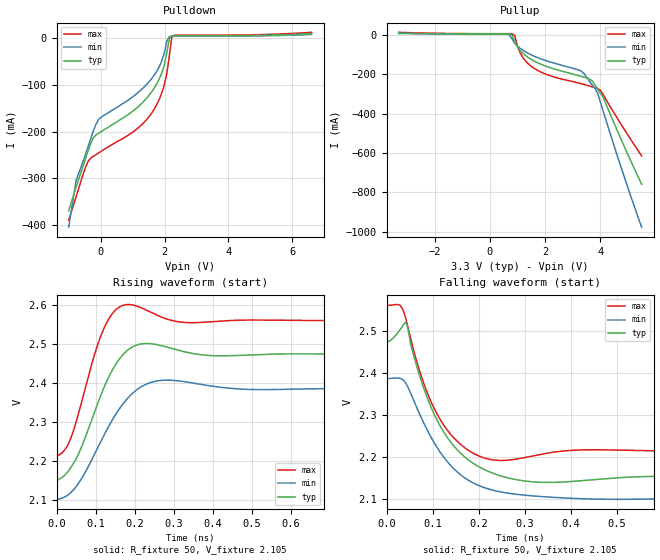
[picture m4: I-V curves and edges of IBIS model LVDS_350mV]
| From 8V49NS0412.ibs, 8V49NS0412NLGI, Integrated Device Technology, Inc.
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[Model]   LVDS_350mV
Model_type   Output
Polarity   Non-Inverting
|   typ   min   max
C_comp   2pF   1.5pF   2.5pF
Vmeas = 2.320V
Rref = 50
Cref = 0
Vref = 2.320V
|   typ   min   max
[Voltage range]   3.3V   3.135V   3.465V
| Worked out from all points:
|   slope of the pulldown table from 0 to 0.495 V, typ, clamps not added: 23.4 ohm
|   slope of the pullup table from 0 to 0.495 V, typ, clamps not added: 15.2 kohm
|   rising waveform, R_fixture 50, V_fixture 2.105: 20-80 % time 75.4ps typ, 91.6ps min, 58ps max; typ from 2.15 V to 2.47 V
|   falling waveform, R_fixture 50, V_fixture 2.105: 20-80 % time 86.4ps typ, 98.2ps min, 69.2ps max; typ from 2.47 V to 2.15 V
[Pulldown]
|Voltage   I (typ)   I (min)   I (max)
-1V       -369.2mA   -404mA     -389.3mA
-769.7mV  -318.7mA   -305.5mA   -339.7mA
-385.9mV  -239.3mA   -230.7mA   -262.7mA
-78.79mV  -204mA     -175.3mA   -246.1mA
996mV     -156.6mA   -125.8mA   -201.4mA
1.533V    -120.7mA   -91.73mA   -166.2mA
1.917V    -73.52mA   -48.04mA   -116.3mA
2.071V    -31.23mA   -6.795mA   -75.56mA
2.147V    -1.641mA   2.624mA    -38.4mA
2.224V    4.501mA    3.932mA    1.504mA
2.301V    4.927mA    4.059mA    6.09mA
6.6V      9.632mA    7.787mA    12.38mA
[Pullup]
|Voltage   I (typ)   I (min)   I (max)
-3.3V     9.632mA    7.309mA    13.15mA
600mV     4.967mA    3.931mA    6.255mA
800mV     1.365mA    -18.84mA   6.157mA
900mV     -31.37mA   -41.51mA   -1.956mA
1V        -59.83mA   -56.27mA   -55.59mA
1.2V      -93.01mA   -77.76mA   -115.2mA
1.5V      -124mA     -101mA     -159.1mA
3.3V      -210.2mA   -182.5mA   -247.3mA
3.7V      -232mA     -252.1mA   -263.2mA
3.9V      -273.3mA   -291.9mA   -271.5mA
4.1V      -313.8mA   -383.6mA   -300.7mA
5.5V      -758.3mA   -976.2mA   -614.1mA
[Ramp]
|   typ   min   max
dV/dt_r   0.209/0.084n   0.183/0.101n   0.232/0.067n
dV/dt_f   0.228/0.096n   0.173/0.101n   0.222/0.079n
R_load =   50.0000
[Rising Waveform]
R_fixture = 50
V_fixture   =2.105  |Vcc_typ
V_fixture_min=1.95  |Vcc_min
V_fixture_max=2.15  |Vcc_max
C_fixture = 0.0p
| Time   typ   min   max
0s        2.151V     2.101V     2.213V
38.04ps   2.184V     2.12V      2.262V
96.1ps    2.321V     2.214V     2.468V
122.1ps   2.389V     2.266V     2.54V
148.1ps   2.441V     2.313V     2.583V
176.2ps   2.478V     2.353V     2.6V
220.2ps   2.5V       2.391V     2.59V
280.3ps   2.492V     2.406V     2.564V
416.4ps   2.469V     2.389V     2.557V
2ns       2.473V     2.385V     2.559V
[Falling Waveform]
R_fixture = 50
V_fixture   =2.105  |Vcc_typ
V_fixture_min=1.95  |Vcc_min
V_fixture_max=2.15  |Vcc_max
C_fixture = 0.0p
| Time   typ   min   max
0s        2.474V     2.386V     2.56V
28.03ps   2.501V     2.387V     2.561V
42.04ps   2.519V     2.375V     2.528V
78.08ps   2.372V     2.287V     2.384V
118.1ps   2.27V      2.209V     2.286V
170.2ps   2.199V     2.15V      2.221V
230.2ps   2.161V     2.121V     2.193V
348.3ps   2.139V     2.104V     2.209V
600.6ps   2.154V     2.1V       2.214V
2ns       2.152V     2.102V     2.214V
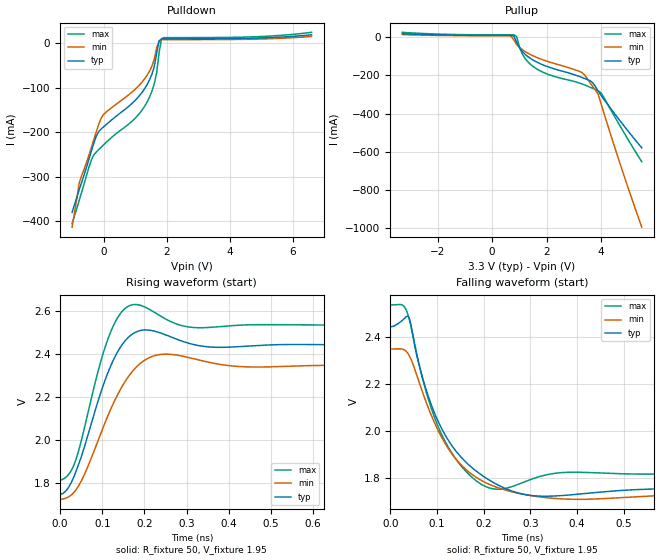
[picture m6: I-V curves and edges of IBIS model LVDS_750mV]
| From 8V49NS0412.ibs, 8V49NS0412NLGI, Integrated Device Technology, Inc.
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[Model]   LVDS_750mV
Model_type   Output
Polarity   Non-Inverting
|   typ   min   max
C_comp   2pF   1.5pF   2.5pF
Vmeas = 2.138V
Rref = 50
Cref = 0
Vref = 2.138V
|   typ   min   max
[Voltage range]   3.3V   3.135V   3.465V
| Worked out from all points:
|   slope of the pulldown table from 0 to 0.495 V, typ, clamps not added: 16.9 ohm
|   slope of the pullup table from 0 to 0.495 V, typ, clamps not added: 7.22 kohm
|   rising waveform, R_fixture 50, V_fixture 1.95: 20-80 % time 67ps typ, 79.6ps min, 55ps max; typ from 1.75 V to 2.44 V
|   falling waveform, R_fixture 50, V_fixture 1.95: 20-80 % time 91.2ps typ, 95.3ps min, 66.1ps max; typ from 2.44 V to 1.75 V
[Pulldown]
|Voltage   I (typ)   I (min)   I (max)
-1V       -380mA     -413.5mA   -405.5mA
-769.7mV  -328.1mA   -312.7mA   -351.9mA
-385.9mV  -241.5mA   -233.6mA   -261.8mA
-232.3mV  -208.5mA   -198.5mA   -244.3mA
-78.79mV  -192.7mA   -168.3mA   -233.6mA
1.303V    -101.7mA   -79.42mA   -141.3mA
1.61V     -51.32mA   -35.06mA   -89.79mA
1.687V    -19.97mA   -8.889mA   -64.63mA
1.764V    6.109mA    5.691mA    -18.81mA
1.84V     10.09mA    8.231mA    11.05mA
1.917V    10.34mA    8.49mA     12.96mA
6.6V      19.39mA    15.63mA    24.98mA
[Pullup]
|Voltage   I (typ)   I (min)   I (max)
-3.3V     19.39mA    14.69mA    26.51mA
600mV     10.43mA    8.42mA     13.14mA
800mV     6.88mA     -13.92mA   13.02mA
900mV     -25.73mA   -36.81mA   4.928mA
1V        -54.29mA   -51.64mA   -48.7mA
1.2V      -87.52mA   -73.19mA   -108.4mA
1.5V      -118.6mA   -96.51mA   -152.2mA
3.3V      -210.1mA   -184.3mA   -244.5mA
3.7V      -238.3mA   -258.5mA   -268mA
3.9V      -282.5mA   -300mA     -280.6mA
4.7V      -437.8mA   -662mA     -464.6mA
5.5V      -579.8mA   -996.1mA   -652.9mA
[Ramp]
|   typ   min   max
dV/dt_r   0.457/0.076n   0.405/0.089n   0.488/0.065n
dV/dt_f   0.46/0.102n   0.384/0.102n   0.471/0.079n
R_load =   50.0000
[Rising Waveform]
R_fixture = 50
V_fixture   =1.95  |Vcc_typ
V_fixture_min=1.75  |Vcc_min
V_fixture_max=2.15  |Vcc_max
C_fixture = 0.0p
| Time   typ   min   max
0s        1.753V     1.725V     1.816V
36.04ps   1.846V     1.765V     1.901V
92.09ps   2.196V     2.009V     2.336V
120.1ps   2.346V     2.145V     2.505V
146.1ps   2.442V     2.247V     2.597V
172.2ps   2.494V     2.322V     2.63V
234.2ps   2.501V     2.397V     2.581V
326.3ps   2.44V      2.374V     2.523V
460.5ps   2.439V     2.34V      2.537V
2ns       2.443V     2.347V     2.535V
[Falling Waveform]
R_fixture = 50
V_fixture   =1.95  |Vcc_typ
V_fixture_min=1.75  |Vcc_min
V_fixture_max=2.15  |Vcc_max
C_fixture = 0.0p
| Time   typ   min   max
0s        2.444V     2.35V      2.537V
26.03ps   2.472V     2.349V     2.536V
40.04ps   2.482V     2.323V     2.481V
76.08ps   2.18V      2.127V     2.172V
122.1ps   1.968V     1.932V     1.939V
170.2ps   1.853V     1.823V     1.812V
220.2ps   1.782V     1.767V     1.754V
292.3ps   1.729V     1.728V     1.788V
386.4ps   1.729V     1.71V      1.825V
2ns       1.755V     1.727V     1.818V
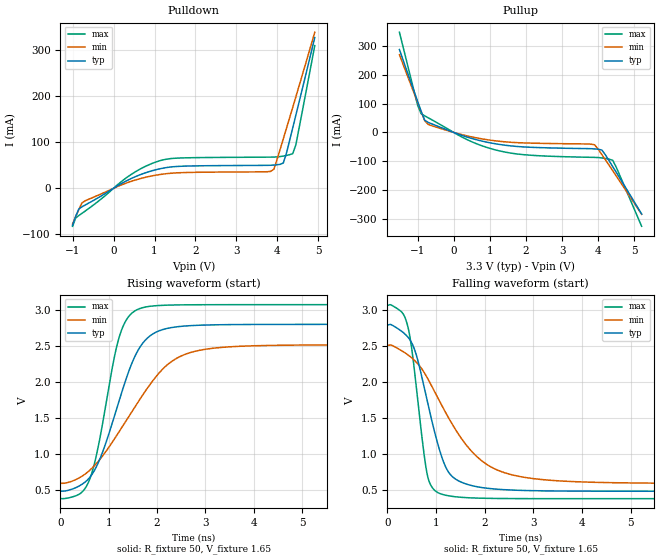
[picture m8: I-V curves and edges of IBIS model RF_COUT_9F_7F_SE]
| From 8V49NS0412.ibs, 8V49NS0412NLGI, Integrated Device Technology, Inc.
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[Model]   RF_COUT_9F_7F_SE
Model_type   Output
Polarity   Non-Inverting
|   typ   min   max
C_comp   2pF   1.5pF   2.5pF
Vmeas = 1.65V
Rref = 50
Cref = 0
Vref = 1.65V
|   typ   min   max
[Voltage range]   3.3V   3.135V   3.465V
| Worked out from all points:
|   slope of the pulldown table from 0 to 0.495 V, typ, clamps not added: 20.8 ohm
|   slope of the pullup table from 0 to 0.495 V, typ, clamps not added: 23.8 ohm
|   rising waveform, R_fixture 50, V_fixture 1.65: 20-80 % time 701ps typ, 1.17ns min, 458ps max; typ from 0.483 V to 2.79 V
|   falling waveform, R_fixture 50, V_fixture 1.65: 20-80 % time 512ps typ, 1.06ns min, 283ps max; typ from 2.79 V to 0.483 V
[Pulldown]
|Voltage   I (typ)   I (min)   I (max)
|Note, modeling breaks down at 250mA and above.  This is well beyond the functional   |
|operating range of the device.  Should this scenario occur, catastrophic failure and   |
|possible damage to the device and/or board is of higher concern than the I-V curve   |
|behavior.  The IBIS checker will flag currents in excess of 10A with warnings.  Lines   |
|with currents in excess of 0.35 A have been commented out.  The points still remain|
|available to the user if the user desires to use them.   |
|Note, modeling breaks down at 250mA and above.  This is well beyond the functional   |
|operating range of the device.  Should this scenario occur, catastrophic failure and   |
|possible damage to the device and/or board is of higher concern than the I-V curve   |
|behavior.  The IBIS checker will flag currents in excess of 10A with warnings.  Lines   |
|with currents in excess of 0.35 A have been commented out.  The points still remain|
|available to the user if the user desires to use them.   |
-1V       -80.01mA   -77.39mA   -82.42mA
-923.2mV  -60.69mA   -61.48mA   -64.31mA
-846.5mV  -44.85mA   -45.55mA   -59.05mA
-692.9mV  -36.28mA   -27.09mA   -49.43mA
381.8mV   19.16mA    13.65mA    27.17mA
1.073V    41.15mA    29.07mA    58.25mA
1.61V     47.69mA    33.79mA    65.71mA
3.913V    50.42mA    41.44mA    67.79mA
4.143V    55mA       107.4mA    69.96mA
4.374V    131.2mA    175.8mA    75.2mA
4.451V    158.9mA    198.7mA    94.62mA
4.911V    327mA      338.5mA    309.5mA
|| 4.98788e+00   3.55369e-01   3.62098e-01   3.45717e-01
|| 5.06465e+00   3.83846e-01   3.85830e-01   3.82046e-01
|| 5.14141e+00   4.12429e-01   4.09675e-01   4.18481e-01
|| 5.21818e+00   4.41121e-01   4.33643e-01   4.55023e-01
|| 5.29495e+00   4.69927e-01   4.57741e-01   4.91672e-01
|| 5.37172e+00   4.98853e-01   4.81982e-01   5.28433e-01
|| 5.44848e+00   5.27906e-01   5.06377e-01   5.65308e-01
|| 5.52525e+00   5.57095e-01   5.30941e-01   6.02303e-01
|| 5.60202e+00   5.86428e-01   5.55693e-01   6.39424e-01
|| 5.67879e+00   6.15919e-01   5.80653e-01   6.76679e-01
|| 5.75556e+00   6.45578e-01   6.05845e-01   7.14075e-01
|| 5.83232e+00   6.75422e-01   6.31297e-01   7.51623e-01
|| 5.90909e+00   7.05468e-01   6.57044e-01   7.89333e-01
|| 5.98586e+00   7.35735e-01   6.83124e-01   8.27218e-01
|| 6.06263e+00   7.66248e-01   7.09586e-01   8.65292e-01
|| 6.13939e+00   7.97032e-01   7.36483e-01   9.03570e-01
|| 6.21616e+00   8.28120e-01   7.63880e-01   9.42072e-01
|| 6.29293e+00   8.59548e-01   7.91844e-01   9.80818e-01
|| 6.36970e+00   8.91358e-01   8.20439e-01   1.01983e+00
|| 6.44646e+00   9.23602e-01   8.49697e-01   1.05914e+00
|| 6.52323e+00   9.56338e-01   8.79569e-01   1.09877e+00
|| 6.60000e+00   9.89634e-01   9.09969e-01   1.13877e+00
[Pullup]
|Voltage   I (typ)   I (min)   I (max)
|Note, modeling breaks down at 250mA and above.  This is well beyond the functional   |
|operating range of the device.  Should this scenario occur, catastrophic failure and   |
|possible damage to the device and/or board is of higher concern than the I-V curve   |
|behavior.  The IBIS checker will flag currents in excess of 10A with warnings.  Lines   |
|with currents in excess of 0.35 A have been commented out.  The points still remain|
|available to the user if the user desires to use them.   |
|-3.30000e+00   9.45857e-01   8.75303e-01   1.27117e+00
|-3.20000e+00   9.09588e-01   8.41674e-01   1.22056e+00
|-3.10000e+00   8.73366e-01   8.08121e-01   1.16996e+00
|-3.00000e+00   8.37177e-01   7.74635e-01   1.11936e+00
|-2.90000e+00   8.01009e-01   7.41201e-01   1.06874e+00
|-2.80000e+00   7.64851e-01   7.07805e-01   1.01810e+00
|-2.70000e+00   7.28692e-01   6.74437e-01   9.67395e-01
|-2.60000e+00   6.92523e-01   6.41088e-01   9.16593e-01
|-2.50000e+00   6.56325e-01   6.07748e-01   8.65519e-01
|-2.40000e+00   6.20062e-01   5.74411e-01   8.13176e-01
|-2.30000e+00   5.83594e-01   5.41061e-01   7.60402e-01
|-2.20000e+00   5.46132e-01   5.07670e-01   7.07979e-01
|-2.10000e+00   5.08522e-01   4.74113e-01   6.55878e-01
|-2.00000e+00   4.71209e-01   4.39722e-01   6.04068e-01
|-1.90000e+00   4.34167e-01   4.05325e-01   5.52519e-01
|-1.80000e+00   3.97370e-01   3.71202e-01   5.01202e-01
|-1.70000e+00   3.60796e-01   3.37331e-01   4.50088e-01
|-1.60000e+00   3.24420e-01   3.03688e-01   3.99149e-01
-1.5V     288.2mA    270.3mA    348.4mA
-1V       109.2mA    105.5mA    95.76mA
-900mV    73.61mA    72.9mA     64.87mA
-800mV    42.22mA    40.41mA    57.54mA
-700mV    34.5mA     27.43mA    50.55mA
400mV     -17.28mA   -12.96mA   -26.81mA
1.2V      -40.51mA   -29.96mA   -62.27mA
2.1V      -51.52mA   -37.13mA   -79.12mA
3.9V      -57.37mA   -43.21mA   -86.91mA
4.1V      -61.33mA   -77.21mA   -88.74mA
4.4V      -119mA     -133.1mA   -96.78mA
5.2V      -283.8mA   -285.1mA   -326.7mA
| 5.30000e+00   -3.04576e-01   -3.04296e-01   -3.56043e-01
| 5.40000e+00   -3.25392e-01   -3.23523e-01   -3.85446e-01
| 5.50000e+00   -3.46244e-01   -3.42791e-01   -4.14886e-01
| 5.60000e+00   -3.67138e-01   -3.62103e-01   -4.44370e-01
| 5.70000e+00   -3.88076e-01   -3.81462e-01   -4.73908e-01
| 5.80000e+00   -4.09065e-01   -4.00872e-01   -5.03509e-01
| 5.90000e+00   -4.30112e-01   -4.20339e-01   -5.33184e-01
| 6.00000e+00   -4.51223e-01   -4.39868e-01   -5.62945e-01
| 6.10000e+00   -4.72405e-01   -4.59465e-01   -5.92805e-01
| 6.20000e+00   -4.93669e-01   -4.79137e-01   -6.22775e-01
| 6.30000e+00   -5.15022e-01   -4.98891e-01   -6.52870e-01
| 6.40000e+00   -5.36474e-01   -5.18735e-01   -6.83105e-01
| 6.50000e+00   -5.58035e-01   -5.38676e-01   -7.13493e-01
| 6.60000e+00   -5.79716e-01   -5.58723e-01   -7.44050e-01
[Ramp]
|   typ   min   max
dV/dt_r   1.386/0.701n   1.151/1.172n   1.612/0.457n
dV/dt_f   1.39/0.513n   1.154/1.062n   1.617/0.284n
R_load =   50.0000
[Rising Waveform]
R_fixture = 50
V_fixture = 1.65   |Vcc_typ
V_fixture_min = 1.5675 |Vcc_min
V_fixture_max = 1.7325 |Vcc_max
C_fixture = 0.0p
| Time   typ   min   max
0s        482.9mV    591.7mV    379.9mV
378.4ps   551.8mV    664mV      437.6mV
576.6ps   650.7mV    755mV      601.7mV
756.8ps   840mV      876.5mV    1.019V
1.225ns   1.76V      1.319V     2.638V
1.423ns   2.161V     1.53V      2.912V
1.73ns    2.555V     1.843V     3.03V
2.432ns   2.762V     2.334V     3.064V
3.514ns   2.791V     2.484V     3.067V
18ns      2.794V     2.511V     3.067V
[Falling Waveform]
R_fixture = 50
V_fixture = 1.65   |Vcc_typ
V_fixture_min = 1.5675 |Vcc_min
V_fixture_max = 1.7325 |Vcc_max
C_fixture = 0.0p
| Time   typ   min   max
0s        2.794V     2.511V     3.067V
396.4ps   2.645V     2.391V     2.833V
486.5ps   2.564V     2.345V     2.539V
576.6ps   2.42V      2.29V      2.049V
828.8ps   1.714V     2.051V     691.1mV
955ps     1.352V     1.89V      508.1mV
1.207ns   809.7mV    1.566V     426.8mV
2.036ns   526.1mV    859.8mV    384.9mV
3.261ns   488mV      640.4mV    380.1mV
18ns      482.9mV    591.7mV    379.9mV
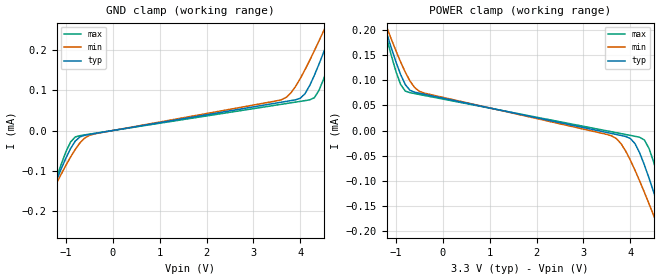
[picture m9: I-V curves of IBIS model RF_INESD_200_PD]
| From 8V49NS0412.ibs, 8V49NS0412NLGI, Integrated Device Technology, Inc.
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[Model]   RF_INESD_200_PD
Model_type   Input
Polarity   Non-Inverting
Vinl = 0.8V
Vinh = 2.0V
|   typ   min   max
C_comp   2pF   1.5pF   2.5pF
|   typ   min   max
[Voltage range]   3.3V   3.135V   3.465V
[GND_clamp]
|Voltage   I (typ)   I (min)   I (max)
|Note, modeling breaks down at 250mA and above.  This is well beyond the functional   |
|operating range of the device.  Should this scenario occur, catastrophic failure and   |
|possible damage to the device and/or board is of higher concern than the I-V curve   |
|behavior.  The IBIS checker will flag currents in excess of 10A with warnings.  Lines   |
|with currents in excess of 0.35 A have been commented out.  The points still remain|
|available to the user if the user desires to use them.   |
-3.3V     -780.9uA   -650.1uA   -919.4uA
-1.8V     -304.1uA   -273.8uA   -338.3uA
-1.6V     -242.3uA   -225.1uA   -262.8uA
-1V       -68.17uA   -86.1uA    -52.64uA
-800mV    -25.99uA   -46.52uA   -15.95uA
-400mV    -7.788uA   -8.613uA   -7.212uA
3.6V      70.1uA     76.32uA    64.91uA
4.2V      111.2uA    173.4uA    75.83uA
4.4V      164.5uA    222uA      99.46uA
4.7V      256.4uA    298.3uA    197.5uA
4.9V      320.8uA    350.4uA    272.9uA
6.6V      892.1uA    808.7uA    956.5uA
[Power_clamp]
|Voltage   I (typ)   I (min)   I (max)
|Note, modeling breaks down at 250mA and above.  This is well beyond the functional   |
|operating range of the device.  Should this scenario occur, catastrophic failure and   |
|possible damage to the device and/or board is of higher concern than the I-V curve   |
|behavior.  The IBIS checker will flag currents in excess of 10A with warnings.  Lines   |
|with currents in excess of 0.35 A have been commented out.  The points still remain|
|available to the user if the user desires to use them.   |
-3.3V     892uA      763.6uA    1.024mA
-1.3V     225uA      230.7uA    221.6uA
-1.2V     194.2uA    205.9uA    184.7uA
-900mV    111.2uA    136.1uA    91.5uA
-700mV    79.87uA    98.22uA    75.12uA
3.6V      -5.841uA   -10.59uA   -2.434uA
4.2V      -44.47uA   -100.2uA   -13.42uA
4.4V      -94.68uA   -145.5uA   -35.71uA
4.6V      -151.8uA   -192.6uA   -94.95uA
4.8V      -211.7uA   -240.8uA   -165uA
4.9V      -242.3uA   -265.2uA   -201.4uA
6.6V      -780.9uA   -692.1uA   -854.8uA
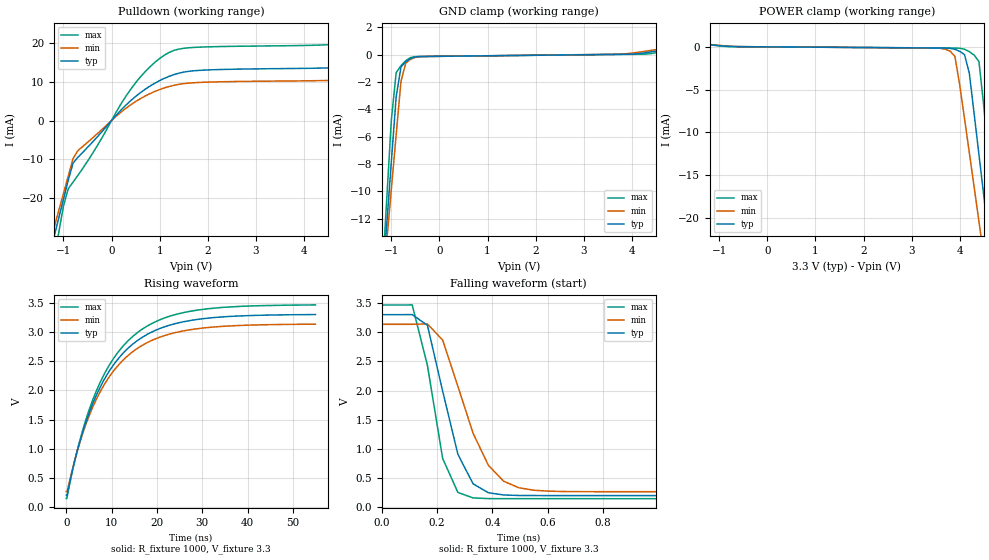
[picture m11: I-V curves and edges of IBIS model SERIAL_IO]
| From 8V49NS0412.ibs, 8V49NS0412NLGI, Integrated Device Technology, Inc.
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[Model] SERIAL_IO
Model_type   I/O_open_drain
Polarity   Non-Inverting
|   typ   min   max
C_comp   2pF   1.5pF   2.5pF
|Input
Vinl = 0.8V
Vinh = 2.0V
|Output
Vmeas = 1.65V
Rref = 5000
Cref = 0
Vref = 3.3V
|   typ   min   max
[Voltage range]   3.3V   3.135V   3.465V
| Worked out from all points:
|   slope of the pulldown table from 0 to 0.495 V, typ, clamps not added: 80.5 ohm
|   GND clamp passes 1 mA (typ) near -0.80 V on its own axis
|   POWER clamp passes 1 mA (typ) near -2.33 V on its own axis
|   rising waveform, R_fixture 1000, V_fixture 3.3: 20-80 % time 11.1ns typ, 11.1ns min, 11.1ns max; typ from 0.202 V to 3.3 V
|   falling waveform, R_fixture 1000, V_fixture 3.3: 20-80 % time 98.3ps typ, 132ps min, 77.2ps max; typ from 3.3 V to 0.202 V
[GND_clamp]
|Voltage   I (typ)   I (min)   I (max)
|Note, modeling breaks down at 250mA and above.  This is well beyond the functional   |
|operating range of the device.  Should this scenario occur, catastrophic failure and   |
|possible damage to the device and/or board is of higher concern than the I-V curve   |
|behavior.  The IBIS checker will flag currents in excess of 10A with warnings.  Lines   |
|with currents in excess of 0.35 A have been commented out.  The points still remain|
|available to the user if the user desires to use them.   |
-3.3V     -120.1mA   -104.4mA   -146.1mA
-1.2V     -17.4mA    -17.85mA   -16.9mA
-1.1V     -12.6mA    -13.82mA   -10.82mA
-1V       -7.826mA   -9.83mA    -4.78mA
-900mV    -3.097mA   -5.869mA   -1.329mA
-800mV    -907.8uA   -1.951mA   -813.2uA
-700mV    -522.7uA   -626.2uA   -443.8uA
-600mV    -283.7uA   -342.2uA   -218.1uA
-400mV    -146.1uA   -152.2uA   -139.6uA
3.7V      15.58uA    25.41uA    8.474uA
4.3V      144.3uA    253.7uA    37.42uA
6.6V      1.656mA    1.582mA    1.788mA
[Power_clamp]
|Voltage   I (typ)   I (min)   I (max)
|Note, modeling breaks down at 250mA and above.  This is well beyond the functional   |
|operating range of the device.  Should this scenario occur, catastrophic failure and   |
|possible damage to the device and/or board is of higher concern than the I-V curve   |
|behavior.  The IBIS checker will flag currents in excess of 10A with warnings.  Lines   |
|with currents in excess of 0.35 A have been commented out.  The points still remain|
|available to the user if the user desires to use them.   |
-3.3V     1.656mA    1.484mA    1.923mA
-900mV    93.8uA     123.4uA    58.06uA
3.7V      -146.1uA   -277.6uA   -133.4uA
3.9V      -283.7uA   -1.11mA    -141.5uA
4.1V      -907.8uA   -8.4mA     -277.5uA
4.2V      -3.097mA   -12.38mA   -559.4uA
4.4V      -12.6mA    -20.43mA   -1.708mA
4.5V      -17.4mA    -24.48mA   -6.891mA
4.6V      -22.22mA   -28.55mA   -12.95mA
4.7V      -27.05mA   -32.63mA   -19.03mA
4.8V      -31.9mA    -36.72mA   -25.14mA
6.6V      -120.1mA   -111.3mA   -135.9mA
[Pulldown]
|Voltage   I (typ)   I (min)   I (max)
|Note, modeling breaks down at 250mA and above.  This is well beyond the functional   |
|operating range of the device.  Should this scenario occur, catastrophic failure and   |
|possible damage to the device and/or board is of higher concern than the I-V curve   |
|behavior.  The IBIS checker will flag currents in excess of 10A with warnings.  Lines   |
|with currents in excess of 0.35 A have been commented out.  The points still remain|
|available to the user if the user desires to use them.   |
-3.3V     -130.8mA   -120.6mA   -175.6mA
-1.3V     -35.07mA   -32.27mA   -42.9mA
-1.2V     -30.19mA   -27.82mA   -36.01mA
-1.1V     -25.28mA   -23.34mA   -29.07mA
-900mV    -15.4mA    -14.33mA   -17.59mA
-800mV    -11mA      -9.8mA     -15.89mA
-700mV    -9.481mA   -7.782mA   -14.16mA
400mV     5.141mA    4.057mA    8.078mA
1.2V      11.41mA    8.788mA    17.58mA
1.9V      12.99mA    9.863mA    18.97mA
5.1V      13.85mA    10.56mA    20.03mA
6.6V      16.29mA    12.49mA    23.98mA
[Ramp]
|   typ   min   max
dV/dt_r   1.857/11.112n   1.718/11.113n   1.989/11.111n
dV/dt_f   1.859/0.098n   1.723/0.132n   1.99/0.077n
R_load =   50.0000
[Rising Waveform]
R_fixture = 1000
V_fixture = 3.3
V_fixture_min = 3.135
V_fixture_max = 3.465
C_fixture = 0.0p
| Time   typ   min   max
0s        202.3mV    269.1mV    149.7mV
220.2ps   226.2mV    272.4mV    188.2mV
1.762ns   762.4mV    772.7mV    759.7mV
3.303ns   1.205V     1.185V     1.232V
6.717ns   1.93V      1.859V     2.004V
10.79ns   2.475V     2.366V     2.585V
15.64ns   2.848V     2.714V     2.983V
21.25ns   3.075V     2.926V     3.226V
28.52ns   3.209V     3.05V      3.368V
55ns      3.297V     3.132V     3.461V
[Falling Waveform]
R_fixture = 1000
V_fixture = 3.3
V_fixture_min = 3.135
V_fixture_max = 3.465
C_fixture = 0.0p
| Time   typ   min   max
0s        3.3V       3.135V     3.465V
110.1ps   3.301V     3.135V     3.467V
165.2ps   3.118V     3.141V     2.432V
220.2ps   1.992V     2.865V     839.1mV
275.3ps   910.6mV    2.073V     256.5mV
330.3ps   403.6mV    1.269V     163mV
385.4ps   251.5mV    723mV      151mV
495.5ps   204.8mV    336.7mV    149.8mV
770.8ps   202.4mV    269.4mV    149.5mV
55ns      202.3mV    269.1mV    149.7mV
